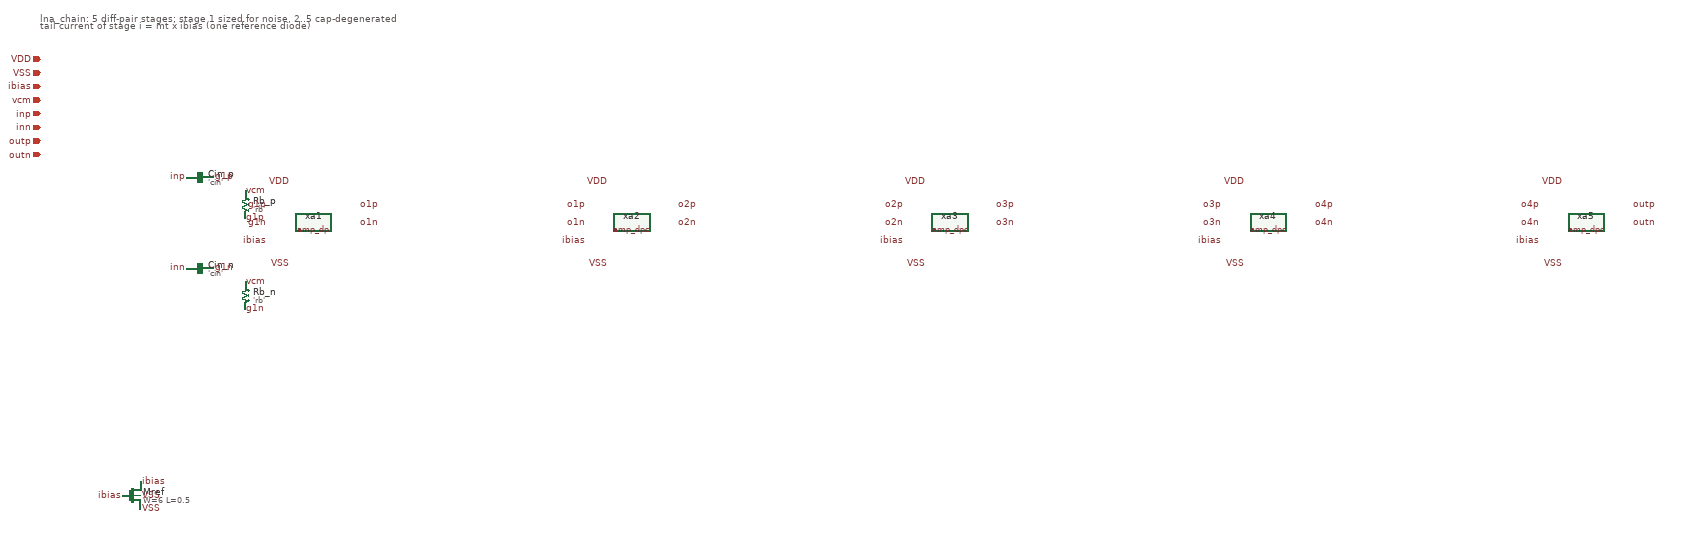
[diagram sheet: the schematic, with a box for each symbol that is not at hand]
v {xschem version=3.4.5 file_version=1.2
}
G {}
K {}
V {}
S {}
E {}
T {lna_chain: 5 diff-pair stages; stage 1 sized for noise, 2..5 cap-degenerated
tail current of stage i = mt x ibias (one reference diode)} -600 -760 0 0 0.4 0.4 {}
C {devices/iopin.sym} -600 -660 0 0 {name=p1
lab=VDD}
C {devices/iopin.sym} -600 -630 0 0 {name=p2
lab=VSS}
C {devices/iopin.sym} -600 -600 0 0 {name=p3
lab=ibias}
C {devices/iopin.sym} -600 -570 0 0 {name=p4
lab=vcm}
C {devices/iopin.sym} -600 -540 0 0 {name=p5
lab=inp}
C {devices/iopin.sym} -600 -510 0 0 {name=p6
lab=inn}
C {devices/iopin.sym} -600 -480 0 0 {name=p7
lab=outp}
C {devices/iopin.sym} -600 -450 0 0 {name=p8
lab=outn}
C {sky130_fd_pr/nfet_01v8.sym} -400 300 0 0 {name=Mref
nf=2
mult=1
ad="'int((nf+1)/2) * W/nf * 0.29'"
pd="'2*int((nf+1)/2) * (W/nf + 0.29)'"
as="'int((nf+2)/2) * W/nf * 0.29'"
ps="'2*int((nf+2)/2) * (W/nf + 0.29)'"
nrd="'0.29 / W'"
nrs="'0.29 / W'"
sa=0
sb=0
sd=0
L=0.5
W=6
model=nfet_01v8
spiceprefix=X}
C {devices/lab_pin.sym} -380 270 0 1 {name=p9
sig_type=std_logic
lab=ibias}
C {devices/lab_pin.sym} -420 300 0 0 {name=p10
sig_type=std_logic
lab=ibias}
C {devices/lab_pin.sym} -380 330 0 1 {name=p11
sig_type=std_logic
lab=VSS}
C {devices/lab_pin.sym} -380 300 0 1 {name=p12
sig_type=std_logic
lab=VSS}
C {devices/capa.sym} -250 -400 1 0 {name=Cin_p
value='cin'
m=1}
C {devices/lab_pin.sym} -220 -400 0 1 {name=p13
sig_type=std_logic
lab=g1p}
C {devices/lab_pin.sym} -280 -400 0 0 {name=p14
sig_type=std_logic
lab=inp}
C {devices/res.sym} -150 -340 0 0 {name=Rb_p
value='rb'
m=1}
C {devices/lab_pin.sym} -150 -370 0 1 {name=p15
sig_type=std_logic
lab=vcm}
C {devices/lab_pin.sym} -150 -310 0 1 {name=p16
sig_type=std_logic
lab=g1p}
C {devices/capa.sym} -250 -200 1 0 {name=Cin_n
value='cin'
m=1}
C {devices/lab_pin.sym} -220 -200 0 1 {name=p17
sig_type=std_logic
lab=g1n}
C {devices/lab_pin.sym} -280 -200 0 0 {name=p18
sig_type=std_logic
lab=inn}
C {devices/res.sym} -150 -140 0 0 {name=Rb_n
value='rb'
m=1}
C {devices/lab_pin.sym} -150 -170 0 1 {name=p19
sig_type=std_logic
lab=vcm}
C {devices/lab_pin.sym} -150 -110 0 1 {name=p20
sig_type=std_logic
lab=g1n}
C {amp_dp.sym} 0 -300 0 0 {name=xa1
w='w1'
l=0.15
rl='rl1'
wt=6
mt='mt1'}
C {devices/lab_pin.sym} -100 -340 0 0 {name=p21
sig_type=std_logic
lab=g1p}
C {devices/lab_pin.sym} -100 -300 0 0 {name=p22
sig_type=std_logic
lab=g1n}
C {devices/lab_pin.sym} -100 -260 0 0 {name=p23
sig_type=std_logic
lab=ibias}
C {devices/lab_pin.sym} 100 -340 0 1 {name=p24
sig_type=std_logic
lab=o1p}
C {devices/lab_pin.sym} 100 -300 0 1 {name=p25
sig_type=std_logic
lab=o1n}
C {devices/lab_pin.sym} -50 -390 0 0 {name=p26
sig_type=std_logic
lab=VDD}
C {devices/lab_pin.sym} -50 -210 0 0 {name=p27
sig_type=std_logic
lab=VSS}
C {amp_dpc.sym} 700 -300 0 0 {name=xa2
w='w2'
l=0.15
rl='rl2'
wt=6
mt='mt2'
cs='cs'}
C {devices/lab_pin.sym} 600 -340 0 0 {name=p28
sig_type=std_logic
lab=o1p}
C {devices/lab_pin.sym} 600 -300 0 0 {name=p29
sig_type=std_logic
lab=o1n}
C {devices/lab_pin.sym} 600 -260 0 0 {name=p30
sig_type=std_logic
lab=ibias}
C {devices/lab_pin.sym} 800 -340 0 1 {name=p31
sig_type=std_logic
lab=o2p}
C {devices/lab_pin.sym} 800 -300 0 1 {name=p32
sig_type=std_logic
lab=o2n}
C {devices/lab_pin.sym} 650 -390 0 0 {name=p33
sig_type=std_logic
lab=VDD}
C {devices/lab_pin.sym} 650 -210 0 0 {name=p34
sig_type=std_logic
lab=VSS}
C {amp_dpc.sym} 1400 -300 0 0 {name=xa3
w='w2'
l=0.15
rl='rl2'
wt=6
mt='mt2'
cs='cs'}
C {devices/lab_pin.sym} 1300 -340 0 0 {name=p35
sig_type=std_logic
lab=o2p}
C {devices/lab_pin.sym} 1300 -300 0 0 {name=p36
sig_type=std_logic
lab=o2n}
C {devices/lab_pin.sym} 1300 -260 0 0 {name=p37
sig_type=std_logic
lab=ibias}
C {devices/lab_pin.sym} 1500 -340 0 1 {name=p38
sig_type=std_logic
lab=o3p}
C {devices/lab_pin.sym} 1500 -300 0 1 {name=p39
sig_type=std_logic
lab=o3n}
C {devices/lab_pin.sym} 1350 -390 0 0 {name=p40
sig_type=std_logic
lab=VDD}
C {devices/lab_pin.sym} 1350 -210 0 0 {name=p41
sig_type=std_logic
lab=VSS}
C {amp_dpc.sym} 2100 -300 0 0 {name=xa4
w='w2'
l=0.15
rl='rl2'
wt=6
mt='mt2'
cs='cs'}
C {devices/lab_pin.sym} 2000 -340 0 0 {name=p42
sig_type=std_logic
lab=o3p}
C {devices/lab_pin.sym} 2000 -300 0 0 {name=p43
sig_type=std_logic
lab=o3n}
C {devices/lab_pin.sym} 2000 -260 0 0 {name=p44
sig_type=std_logic
lab=ibias}
C {devices/lab_pin.sym} 2200 -340 0 1 {name=p45
sig_type=std_logic
lab=o4p}
C {devices/lab_pin.sym} 2200 -300 0 1 {name=p46
sig_type=std_logic
lab=o4n}
C {devices/lab_pin.sym} 2050 -390 0 0 {name=p47
sig_type=std_logic
lab=VDD}
C {devices/lab_pin.sym} 2050 -210 0 0 {name=p48
sig_type=std_logic
lab=VSS}
C {amp_dpc.sym} 2800 -300 0 0 {name=xa5
w='w2'
l=0.15
rl='rl2'
wt=6
mt='mt2'
cs='cs'}
C {devices/lab_pin.sym} 2700 -340 0 0 {name=p49
sig_type=std_logic
lab=o4p}
C {devices/lab_pin.sym} 2700 -300 0 0 {name=p50
sig_type=std_logic
lab=o4n}
C {devices/lab_pin.sym} 2700 -260 0 0 {name=p51
sig_type=std_logic
lab=ibias}
C {devices/lab_pin.sym} 2900 -340 0 1 {name=p52
sig_type=std_logic
lab=outp}
C {devices/lab_pin.sym} 2900 -300 0 1 {name=p53
sig_type=std_logic
lab=outn}
C {devices/lab_pin.sym} 2750 -390 0 0 {name=p54
sig_type=std_logic
lab=VDD}
C {devices/lab_pin.sym} 2750 -210 0 0 {name=p55
sig_type=std_logic
lab=VSS}
